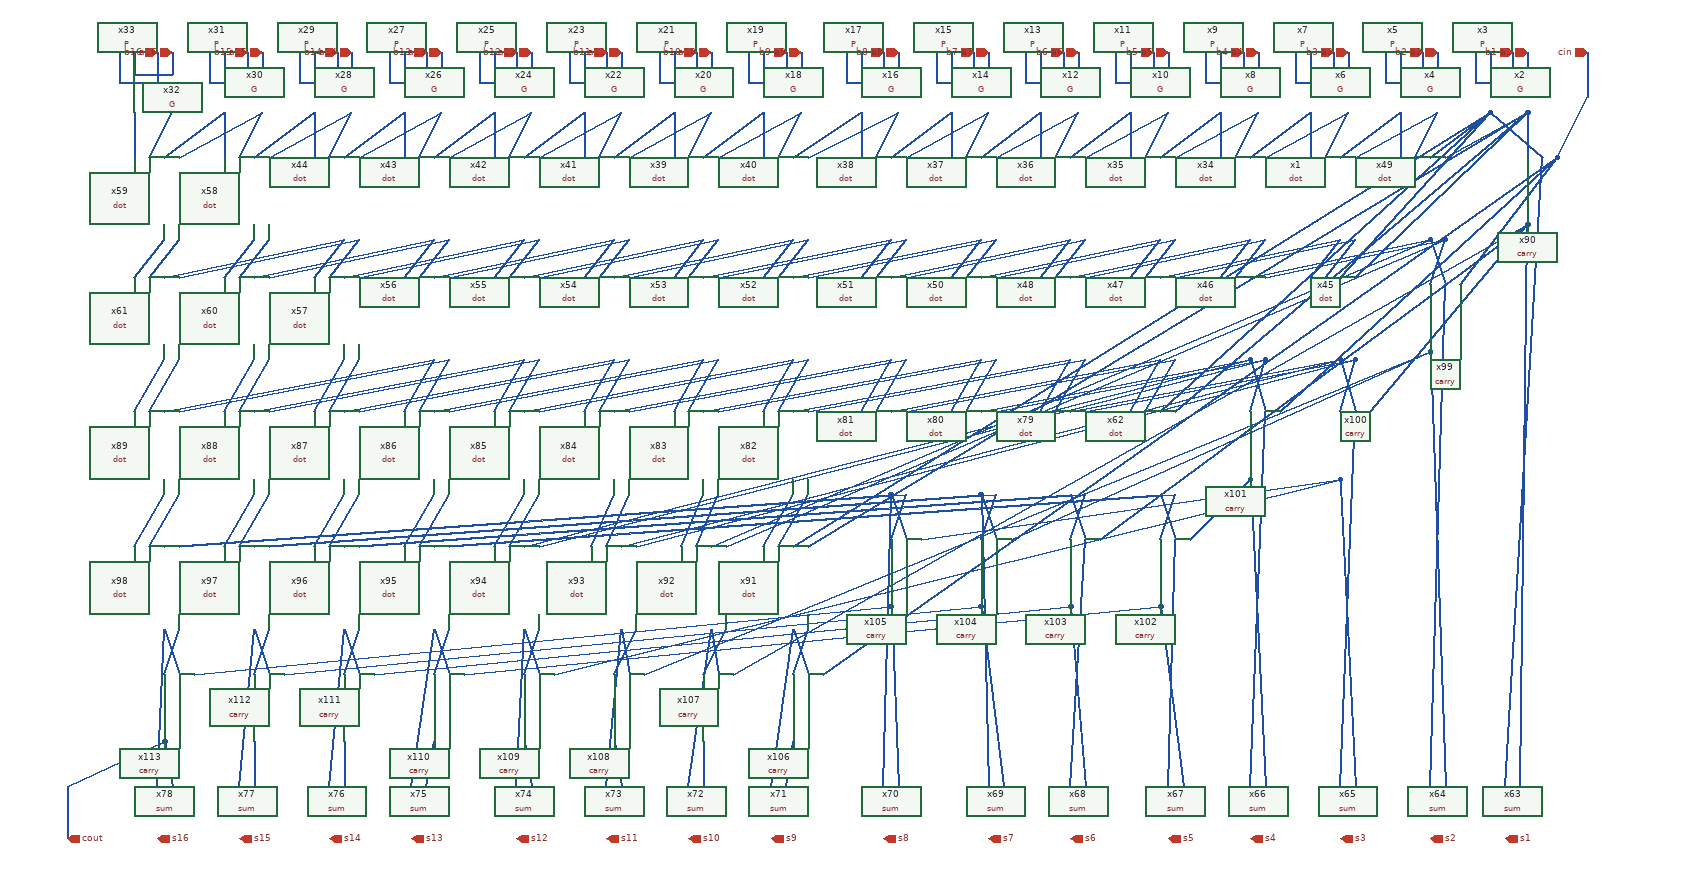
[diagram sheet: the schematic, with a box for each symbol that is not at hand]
v {xschem version=3.4.6 file_version=1.2}
G {}
K {}
V {}
S {}
E {}
N 1020 -110 1020 -50 {lab=cin}
N 940 -110 940 -80 {lab=a1}
N 890 -80 940 -80 {lab=a1}
N 890 -110 890 -80 {lab=a1}
N 920 -110 920 -70 {lab=b1}
N 870 -70 920 -70 {lab=b1}
N 870 -110 870 -70 {lab=b1}
N 820 -110 820 -80 {lab=a2}
N 770 -80 820 -80 {lab=a2}
N 770 -110 770 -80 {lab=a2}
N 800 -110 800 -70 {lab=b2}
N 750 -70 800 -70 {lab=b2}
N 750 -110 750 -70 {lab=b2}
N 700 -110 700 -80 {lab=a3}
N 650 -80 700 -80 {lab=a3}
N 650 -110 650 -80 {lab=a3}
N 680 -110 680 -70 {lab=b3}
N 630 -70 680 -70 {lab=b3}
N 630 -110 630 -70 {lab=b3}
N 580 -110 580 -80 {lab=a4}
N 530 -80 580 -80 {lab=a4}
N 530 -110 530 -80 {lab=a4}
N 560 -110 560 -70 {lab=b4}
N 510 -70 560 -70 {lab=b4}
N 510 -110 510 -70 {lab=b4}
N 460 -110 460 -80 {lab=a5}
N 410 -80 460 -80 {lab=a5}
N 410 -110 410 -80 {lab=a5}
N 440 -110 440 -70 {lab=b5}
N 390 -70 440 -70 {lab=b5}
N 390 -110 390 -70 {lab=b5}
N 340 -110 340 -80 {lab=a6}
N 290 -80 340 -80 {lab=a6}
N 290 -110 290 -80 {lab=a6}
N 320 -110 320 -70 {lab=b6}
N 270 -70 320 -70 {lab=b6}
N 270 -110 270 -70 {lab=b6}
N 220 -110 220 -80 {lab=a7}
N 170 -80 220 -80 {lab=a7}
N 170 -110 170 -80 {lab=a7}
N 200 -110 200 -70 {lab=b7}
N 150 -70 200 -70 {lab=b7}
N 150 -110 150 -70 {lab=b7}
N 100 -110 100 -80 {lab=a8}
N 50 -80 100 -80 {lab=a8}
N 50 -110 50 -80 {lab=a8}
N 80 -110 80 -70 {lab=b8}
N 30 -70 80 -70 {lab=b8}
N 30 -110 30 -70 {lab=b8}
N -30 -110 -30 -80 {lab=a9}
N -80 -80 -30 -80 {lab=a9}
N -80 -110 -80 -80 {lab=a9}
N -50 -110 -50 -70 {lab=b9}
N -100 -70 -50 -70 {lab=b9}
N -100 -110 -100 -70 {lab=b9}
N -150 -110 -150 -80 {lab=a10}
N -200 -80 -150 -80 {lab=a10}
N -200 -110 -200 -80 {lab=a10}
N -170 -110 -170 -70 {lab=b10}
N -220 -70 -170 -70 {lab=b10}
N -220 -110 -220 -70 {lab=b10}
N -270 -110 -270 -80 {lab=a11}
N -320 -80 -270 -80 {lab=a11}
N -320 -110 -320 -80 {lab=a11}
N -290 -110 -290 -70 {lab=b11}
N -340 -70 -290 -70 {lab=b11}
N -340 -110 -340 -70 {lab=b11}
N -390 -110 -390 -80 {lab=a12}
N -440 -80 -390 -80 {lab=a12}
N -440 -110 -440 -80 {lab=a12}
N -410 -110 -410 -70 {lab=b12}
N -460 -70 -410 -70 {lab=b12}
N -460 -110 -460 -70 {lab=b12}
N -510 -110 -510 -80 {lab=a13}
N -560 -80 -510 -80 {lab=a13}
N -560 -110 -560 -80 {lab=a13}
N -530 -110 -530 -70 {lab=b13}
N -580 -70 -530 -70 {lab=b13}
N -580 -110 -580 -70 {lab=b13}
N -630 -110 -630 -80 {lab=a14}
N -680 -80 -630 -80 {lab=a14}
N -680 -110 -680 -80 {lab=a14}
N -650 -110 -650 -70 {lab=b14}
N -700 -70 -650 -70 {lab=b14}
N -700 -110 -700 -70 {lab=b14}
N -750 -110 -750 -80 {lab=a15}
N -800 -80 -750 -80 {lab=a15}
N -800 -110 -800 -80 {lab=a15}
N -770 -110 -770 -70 {lab=b15}
N -820 -70 -770 -70 {lab=b15}
N -820 -110 -820 -70 {lab=b15}
N -870 -110 -870 -80 {lab=a16}
N -920 -80 -870 -80 {lab=a16}
N -920 -110 -920 -80 {lab=a16}
N -890 -110 -890 -70 {lab=b16}
N -940 -70 -890 -70 {lab=b16}
N -940 -110 -940 -70 {lab=b16}
N -1010 870 -1010 940 {lab=cout}
N 770 -30 770 30 {lab=#net1}
N 790 30 820 -30 {lab=#net2}
N 810 30 890 -30 {lab=#net3}
N 830 30 940 -30 {lab=#net4}
N 650 -30 650 30 {lab=#net5}
N 670 30 700 -30 {lab=#net6}
N 690 30 770 -30 {lab=#net1}
N 710 30 820 -30 {lab=#net2}
N 530 -30 530 30 {lab=#net7}
N 550 30 580 -30 {lab=#net8}
N 570 30 650 -30 {lab=#net5}
N 590 30 700 -30 {lab=#net6}
N 410 -30 410 30 {lab=#net9}
N 430 30 460 -30 {lab=#net10}
N 450 30 530 -30 {lab=#net7}
N 470 30 580 -30 {lab=#net8}
N 290 -30 290 30 {lab=#net11}
N 310 30 340 -30 {lab=#net12}
N 330 30 410 -30 {lab=#net9}
N 350 30 460 -30 {lab=#net10}
N 170 -30 170 30 {lab=#net13}
N 190 30 220 -30 {lab=#net14}
N 210 30 290 -30 {lab=#net11}
N 230 30 340 -30 {lab=#net12}
N 50 -30 50 30 {lab=#net15}
N 70 30 100 -30 {lab=#net16}
N 90 30 170 -30 {lab=#net13}
N 110 30 220 -30 {lab=#net14}
N -200 -30 -200 30 {lab=#net17}
N -180 30 -150 -30 {lab=#net18}
N -160 30 -80 -30 {lab=#net19}
N -140 30 -30 -30 {lab=#net20}
N -80 -30 -80 30 {lab=#net19}
N -60 30 -30 -30 {lab=#net20}
N -40 30 50 -30 {lab=#net15}
N -20 30 100 -30 {lab=#net16}
N -320 -30 -320 30 {lab=#net21}
N -300 30 -270 -30 {lab=#net22}
N -280 30 -200 -30 {lab=#net17}
N -260 30 -150 -30 {lab=#net18}
N -440 -30 -440 30 {lab=#net23}
N -420 30 -390 -30 {lab=#net24}
N -400 30 -320 -30 {lab=#net21}
N -380 30 -270 -30 {lab=#net22}
N -560 -30 -560 30 {lab=#net25}
N -540 30 -510 -30 {lab=#net26}
N -520 30 -440 -30 {lab=#net23}
N -500 30 -390 -30 {lab=#net24}
N -680 -30 -680 30 {lab=#net27}
N -660 30 -630 -30 {lab=#net28}
N -640 30 -560 -30 {lab=#net25}
N -620 30 -510 -30 {lab=#net26}
N 710 190 940 -30 {lab=#net4}
N 690 190 890 -30 {lab=#net3}
N 670 190 710 140 {lab=#net29}
N 650 190 690 140 {lab=#net30}
N 530 190 570 140 {lab=#net31}
N 550 190 590 140 {lab=#net32}
N 570 190 810 140 {lab=#net33}
N 590 190 830 140 {lab=#net34}
N 410 190 450 140 {lab=#net35}
N 430 190 470 140 {lab=#net36}
N 450 190 690 140 {lab=#net30}
N 470 190 710 140 {lab=#net29}
N 290 190 330 140 {lab=#net37}
N 310 190 350 140 {lab=#net38}
N 330 190 570 140 {lab=#net31}
N 350 190 590 140 {lab=#net32}
N 170 190 210 140 {lab=#net39}
N 190 190 230 140 {lab=#net40}
N 210 190 450 140 {lab=#net35}
N 230 190 470 140 {lab=#net36}
N 50 190 90 140 {lab=#net41}
N 70 190 110 140 {lab=#net42}
N 90 190 330 140 {lab=#net37}
N 110 190 350 140 {lab=#net38}
N -80 190 -40 140 {lab=#net43}
N -60 190 -20 140 {lab=#net44}
N -40 190 210 140 {lab=#net39}
N -20 190 230 140 {lab=#net40}
N -200 190 -160 140 {lab=#net45}
N -180 190 -140 140 {lab=#net46}
N -160 190 90 140 {lab=#net41}
N -140 190 110 140 {lab=#net42}
N -320 190 -280 140 {lab=#net47}
N -300 190 -260 140 {lab=#net48}
N -280 190 -40 140 {lab=#net43}
N -260 190 -20 140 {lab=#net44}
N -440 190 -400 140 {lab=#net49}
N -420 190 -380 140 {lab=#net50}
N -400 190 -160 140 {lab=#net45}
N -380 190 -140 140 {lab=#net46}
N -560 190 -520 140 {lab=#net51}
N -540 190 -500 140 {lab=#net52}
N -520 190 -280 140 {lab=#net47}
N -500 190 -260 140 {lab=#net48}
N -680 190 -640 140 {lab=#net53}
N -660 190 -620 140 {lab=#net54}
N -640 190 -400 140 {lab=#net49}
N -620 190 -380 140 {lab=#net50}
N -800 -30 -800 30 {lab=#net55}
N -780 30 -750 -30 {lab=#net56}
N -760 30 -680 -30 {lab=#net27}
N -740 30 -630 -30 {lab=#net28}
N -920 -30 -920 30 {lab=#net57}
N -900 30 -870 -30 {lab=#net58}
N -880 30 -800 -30 {lab=#net55}
N -860 30 -750 -30 {lab=#net56}
N -800 190 -760 140 {lab=#net59}
N -780 190 -740 140 {lab=#net60}
N -760 190 -520 140 {lab=#net51}
N -740 190 -500 140 {lab=#net52}
N -920 190 -880 140 {lab=#net61}
N -900 190 -860 140 {lab=#net62}
N -880 190 -640 140 {lab=#net53}
N -860 190 -620 140 {lab=#net54}
N 470 370 940 -30 {lab=#net4}
N 450 370 890 -30 {lab=#net3}
N 430 370 470 300 {lab=#net63}
N 410 370 450 300 {lab=#net64}
N 290 370 330 300 {lab=#net65}
N 310 370 350 300 {lab=#net66}
N 330 370 690 300 {lab=#net67}
N 350 370 710 300 {lab=#net68}
N 170 370 210 300 {lab=#net69}
N 190 370 230 300 {lab=#net70}
N 210 370 570 300 {lab=#net71}
N 230 370 590 300 {lab=#net72}
N 50 370 90 300 {lab=#net73}
N 70 370 110 300 {lab=#net74}
N 90 370 450 300 {lab=#net64}
N 110 370 470 300 {lab=#net63}
N -80 370 -40 300 {lab=#net75}
N -60 370 -20 300 {lab=#net76}
N -200 370 -160 300 {lab=#net77}
N -180 370 -140 300 {lab=#net78}
N -40 370 330 300 {lab=#net65}
N -20 370 350 300 {lab=#net66}
N -160 370 210 300 {lab=#net69}
N -140 370 230 300 {lab=#net70}
N -320 370 -280 300 {lab=#net79}
N -300 370 -260 300 {lab=#net80}
N -280 370 90 300 {lab=#net73}
N -260 370 110 300 {lab=#net74}
N -440 370 -400 300 {lab=#net81}
N -420 370 -380 300 {lab=#net82}
N -400 370 -40 300 {lab=#net75}
N -380 370 -20 300 {lab=#net76}
N -560 370 -520 300 {lab=#net83}
N -540 370 -500 300 {lab=#net84}
N -520 370 -160 300 {lab=#net77}
N -500 370 -140 300 {lab=#net78}
N -680 370 -640 300 {lab=#net85}
N -660 370 -620 300 {lab=#net86}
N -640 370 -280 300 {lab=#net79}
N -620 370 -260 300 {lab=#net80}
N -800 370 -760 300 {lab=#net87}
N -780 370 -740 300 {lab=#net88}
N -760 370 -400 300 {lab=#net81}
N -740 370 -380 300 {lab=#net82}
N -920 370 -880 300 {lab=#net89}
N -900 370 -860 300 {lab=#net90}
N -880 370 -520 300 {lab=#net83}
N -860 370 -500 300 {lab=#net84}
N 940 -30 940 30 {lab=#net4}
N 890 -30 960 30 {lab=#net3}
N 980 30 1020 -50 {lab=cin}
N -20 550 940 -30 {lab=#net4}
N -40 550 890 -30 {lab=#net3}
N -80 550 -40 480 {lab=#net91}
N -60 550 -20 480 {lab=#net92}
N -190 550 -160 480 {lab=#net93}
N -170 550 -140 480 {lab=#net94}
N -150 550 810 140 {lab=#net33}
N -130 550 830 140 {lab=#net34}
N -310 550 -280 480 {lab=#net95}
N -290 550 -260 480 {lab=#net96}
N -270 550 690 300 {lab=#net67}
N -250 550 710 300 {lab=#net68}
N -440 550 -400 480 {lab=#net97}
N -420 550 -380 480 {lab=#net98}
N -400 550 570 300 {lab=#net71}
N -380 550 590 300 {lab=#net72}
N -560 550 -520 480 {lab=#net99}
N -540 550 -500 480 {lab=#net100}
N -520 550 450 480 {lab=#net101}
N -500 550 470 480 {lab=#net102}
N -680 550 -640 480 {lab=#net103}
N -660 550 -620 480 {lab=#net104}
N -640 550 330 480 {lab=#net105}
N -620 550 350 480 {lab=#net106}
N -800 550 -760 480 {lab=#net107}
N -780 550 -740 480 {lab=#net108}
N -760 550 210 480 {lab=#net109}
N -740 550 230 480 {lab=#net110}
N -920 550 -880 480 {lab=#net111}
N -900 550 -860 480 {lab=#net112}
N -880 550 90 480 {lab=#net113}
N -860 550 110 480 {lab=#net114}
N 810 200 830 140 {lab=#net34}
N 810 140 830 200 {lab=#net33}
N 570 370 590 300 {lab=#net72}
N 570 300 590 370 {lab=#net71}
N 690 370 710 300 {lab=#net68}
N 690 300 710 370 {lab=#net67}
N 610 370 980 30 {lab=cin}
N 450 540 470 480 {lab=#net102}
N 450 480 470 540 {lab=#net101}
N 490 540 570 460 {lab=#net115}
N 330 540 350 480 {lab=#net106}
N 330 480 350 540 {lab=#net105}
N 850 200 980 30 {lab=cin}
N 730 370 940 120 {lab=#net116}
N 370 540 940 120 {lab=#net116}
N 250 540 810 290 {lab=#net117}
N 130 540 690 460 {lab=#net118}
N 210 480 230 540 {lab=#net109}
N 210 540 230 480 {lab=#net110}
N 90 480 110 540 {lab=#net113}
N 90 540 110 480 {lab=#net114}
N 0 720 980 30 {lab=cin}
N -120 720 940 120 {lab=#net116}
N -240 720 810 290 {lab=#net117}
N -360 720 690 460 {lab=#net118}
N -480 720 450 630 {lab=#net119}
N -600 720 330 630 {lab=#net120}
N -720 720 210 630 {lab=#net121}
N -840 720 90 630 {lab=#net122}
N -880 660 -860 720 {lab=#net123}
N -880 720 -860 660 {lab=#net124}
N -760 660 -740 720 {lab=#net125}
N -760 720 -740 660 {lab=#net126}
N -640 660 -620 720 {lab=#net127}
N -640 720 -620 660 {lab=#net128}
N -520 660 -500 720 {lab=#net129}
N -520 720 -500 660 {lab=#net130}
N -400 660 -380 720 {lab=#net131}
N -400 720 -380 660 {lab=#net132}
N -270 660 -260 720 {lab=#net133}
N -280 720 -250 660 {lab=#net134}
N -160 720 -130 660 {lab=#net135}
N -150 660 -140 720 {lab=#net136}
N -40 720 -20 660 {lab=#net137}
N -40 660 -20 720 {lab=#net138}
N -880 810 -870 870 {lab=cout}
N -890 870 -880 660 {lab=#net123}
N -780 870 -760 660 {lab=#net125}
N -760 810 -760 870 {lab=#net139}
N -660 870 -640 660 {lab=#net127}
N -640 810 -640 870 {lab=#net140}
N -550 870 -520 660 {lab=#net129}
N -530 870 -520 810 {lab=#net141}
N -400 810 -390 870 {lab=#net142}
N -410 870 -400 660 {lab=#net131}
N -280 810 -270 870 {lab=#net143}
N -290 870 -270 660 {lab=#net133}
N -160 810 -160 870 {lab=#net144}
N -180 870 -150 660 {lab=#net136}
N -50 870 -40 810 {lab=#net145}
N -70 870 -40 660 {lab=#net138}
N 90 630 100 870 {lab=#net122}
N 80 870 90 480 {lab=#net113}
N 210 480 220 870 {lab=#net109}
N 210 630 240 870 {lab=#net121}
N 330 630 350 870 {lab=#net120}
N 330 870 350 540 {lab=#net105}
N 450 630 480 870 {lab=#net119}
N 460 870 470 540 {lab=#net101}
N 570 460 590 870 {lab=#net115}
N 570 870 590 370 {lab=#net71}
N 690 470 710 870 {lab=#net118}
N 690 870 710 370 {lab=#net67}
N 810 290 830 870 {lab=#net117}
N 810 870 830 200 {lab=#net33}
N 930 870 940 120 {lab=#net116}
N 910 870 960 30 {lab=#net3}
N -1010 870 -880 810 {lab=cout}
N 940 120 940 130 {lab=#net116}
N 810 290 810 300 {lab=#net117}
N 90 630 90 640 {lab=#net122}
N 450 630 450 640 {lab=#net119}
N 330 630 330 640 {lab=#net120}
N 570 460 570 470 {lab=#net115}
N 690 460 690 470 {lab=#net118}
N 210 630 210 640 {lab=#net121}
N -520 810 -520 820 {lab=#net141}
N -400 810 -400 820 {lab=#net142}
N -280 810 -280 820 {lab=#net143}
N -880 810 -880 820 {lab=cout}
N -40 810 -40 820 {lab=#net145}
C {G.sym} 930 -70 1 0 {name=x2}
C {P.sym} 880 -70 1 0 {name=x3}
C {G.sym} 810 -70 1 0 {name=x4}
C {P.sym} 760 -70 1 0 {name=x5}
C {G.sym} 690 -70 1 0 {name=x6}
C {P.sym} 640 -70 1 0 {name=x7}
C {G.sym} 570 -70 1 0 {name=x8}
C {P.sym} 520 -70 1 0 {name=x9}
C {G.sym} 450 -70 1 0 {name=x10}
C {P.sym} 400 -70 1 0 {name=x11}
C {G.sym} 330 -70 1 0 {name=x12}
C {P.sym} 280 -70 1 0 {name=x13}
C {G.sym} 210 -70 1 0 {name=x14}
C {P.sym} 160 -70 1 0 {name=x15}
C {G.sym} 90 -70 1 0 {name=x16}
C {P.sym} 40 -70 1 0 {name=x17}
C {G.sym} -40 -70 1 0 {name=x18}
C {P.sym} -90 -70 1 0 {name=x19}
C {G.sym} -160 -70 1 0 {name=x20}
C {P.sym} -210 -70 1 0 {name=x21}
C {G.sym} -280 -70 1 0 {name=x22}
C {P.sym} -330 -70 1 0 {name=x23}
C {G.sym} -400 -70 1 0 {name=x24}
C {P.sym} -450 -70 1 0 {name=x25}
C {G.sym} -520 -70 1 0 {name=x26}
C {P.sym} -570 -70 1 0 {name=x27}
C {G.sym} -640 -70 1 0 {name=x28}
C {P.sym} -690 -70 1 0 {name=x29}
C {G.sym} -760 -70 1 0 {name=x30}
C {P.sym} -810 -70 1 0 {name=x31}
C {G.sym} -880 -70 1 0 {name=x32}
C {P.sym} -930 -70 1 0 {name=x33}
C {sum.sym} 920 900 3 1 {name=x63}
C {sum.sym} 820 900 3 1 {name=x64}
C {sum.sym} 700 900 3 1 {name=x65}
C {sum.sym} 580 900 3 1 {name=x66}
C {sum.sym} 470 900 3 1 {name=x67}
C {sum.sym} 340 900 3 1 {name=x68}
C {sum.sym} 230 900 3 1 {name=x69}
C {sum.sym} 90 900 3 1 {name=x70}
C {sum.sym} -60 900 3 1 {name=x71}
C {sum.sym} -170 900 3 1 {name=x72}
C {sum.sym} -280 900 3 1 {name=x73}
C {sum.sym} -400 900 3 1 {name=x74}
C {sum.sym} -540 900 3 1 {name=x75}
C {sum.sym} -650 900 3 1 {name=x76}
C {sum.sym} -770 900 3 1 {name=x77}
C {sum.sym} -880 900 3 1 {name=x78}
C {ipin.sym} -890 -110 1 0 {name=p3 lab=b16}
C {ipin.sym} -870 -110 1 0 {name=p4 lab=a16}
C {ipin.sym} -770 -110 1 0 {name=p7 lab=b15}
C {ipin.sym} -750 -110 1 0 {name=p8 lab=a15}
C {ipin.sym} -650 -110 1 0 {name=p11 lab=b14}
C {ipin.sym} -630 -110 1 0 {name=p12 lab=a14}
C {ipin.sym} -530 -110 1 0 {name=p15 lab=b13}
C {ipin.sym} -510 -110 1 0 {name=p16 lab=a13}
C {ipin.sym} -410 -110 1 0 {name=p19 lab=b12}
C {ipin.sym} -390 -110 1 0 {name=p20 lab=a12}
C {ipin.sym} -290 -110 1 0 {name=p23 lab=b11}
C {ipin.sym} -270 -110 1 0 {name=p24 lab=a11}
C {ipin.sym} -170 -110 1 0 {name=p27 lab=b10}
C {ipin.sym} -150 -110 1 0 {name=p28 lab=a10}
C {ipin.sym} -50 -110 1 0 {name=p31 lab=b9}
C {ipin.sym} -30 -110 1 0 {name=p32 lab=a9}
C {ipin.sym} 80 -110 1 0 {name=p35 lab=b8}
C {ipin.sym} 100 -110 1 0 {name=p36 lab=a8}
C {ipin.sym} 200 -110 1 0 {name=p39 lab=b7}
C {ipin.sym} 220 -110 1 0 {name=p40 lab=a7}
C {ipin.sym} 320 -110 1 0 {name=p43 lab=b6}
C {ipin.sym} 340 -110 1 0 {name=p44 lab=a6}
C {ipin.sym} 440 -110 1 0 {name=p47 lab=b5}
C {ipin.sym} 460 -110 1 0 {name=p48 lab=a5}
C {ipin.sym} 560 -110 1 0 {name=p51 lab=b4}
C {ipin.sym} 580 -110 1 0 {name=p52 lab=a4}
C {ipin.sym} 680 -110 1 0 {name=p55 lab=b3}
C {ipin.sym} 700 -110 1 0 {name=p56 lab=a3}
C {ipin.sym} 800 -110 1 0 {name=p59 lab=b2}
C {ipin.sym} 820 -110 1 0 {name=p60 lab=a2}
C {ipin.sym} 920 -110 1 0 {name=p63 lab=b1}
C {ipin.sym} 940 -110 1 0 {name=p64 lab=a1}
C {ipin.sym} 1020 -110 1 0 {name=p65 lab=cin}
C {opin.sym} 910 940 1 0 {name=p1 lab=s1}
C {opin.sym} 810 940 1 0 {name=p2 lab=s2}
C {opin.sym} 690 940 1 0 {name=p5 lab=s3}
C {opin.sym} 570 940 1 0 {name=p6 lab=s4}
C {opin.sym} 460 940 1 0 {name=p9 lab=s5}
C {opin.sym} 330 940 1 0 {name=p10 lab=s6}
C {opin.sym} 220 940 1 0 {name=p13 lab=s7}
C {opin.sym} 80 940 1 0 {name=p14 lab=s8}
C {opin.sym} -70 940 1 0 {name=p17 lab=s9}
C {opin.sym} -180 940 1 0 {name=p18 lab=s10}
C {opin.sym} -290 940 1 0 {name=p21 lab=s11}
C {opin.sym} -410 940 1 0 {name=p22 lab=s12}
C {opin.sym} -550 940 1 0 {name=p25 lab=s13}
C {opin.sym} -660 940 1 0 {name=p26 lab=s14}
C {opin.sym} -780 940 1 0 {name=p29 lab=s15}
C {opin.sym} -890 940 1 0 {name=p30 lab=s16}
C {opin.sym} -1010 940 1 0 {name=p33 lab=cout}
C {dot.sym} 800 90 1 0 {name=x49}
C {dot.sym} 680 90 1 0 {name=x1}
C {dot.sym} 560 90 1 0 {name=x34}
C {dot.sym} 440 90 1 0 {name=x35}
C {dot.sym} 320 90 1 0 {name=x36}
C {dot.sym} 200 90 1 0 {name=x37}
C {dot.sym} 80 90 1 0 {name=x38}
C {dot.sym} -170 90 1 0 {name=x39}
C {dot.sym} -50 90 1 0 {name=x40}
C {dot.sym} -290 90 1 0 {name=x41}
C {dot.sym} -410 90 1 0 {name=x42}
C {dot.sym} -530 90 1 0 {name=x43}
C {dot.sym} -650 90 1 0 {name=x44}
C {dot.sym} 680 250 1 0 {name=x45}
C {dot.sym} 560 250 1 0 {name=x46}
C {dot.sym} 440 250 1 0 {name=x47}
C {dot.sym} 320 250 1 0 {name=x48}
C {dot.sym} 200 250 1 0 {name=x50}
C {dot.sym} 80 250 1 0 {name=x51}
C {dot.sym} -50 250 1 0 {name=x52}
C {dot.sym} -170 250 1 0 {name=x53}
C {dot.sym} -290 250 1 0 {name=x54}
C {dot.sym} -410 250 1 0 {name=x55}
C {dot.sym} -530 250 1 0 {name=x56}
C {dot.sym} -650 250 1 0 {name=x57}
C {dot.sym} -770 90 1 0 {name=x58}
C {dot.sym} -890 90 1 0 {name=x59}
C {dot.sym} -770 250 1 0 {name=x60}
C {dot.sym} -890 250 1 0 {name=x61}
C {dot.sym} 440 430 1 0 {name=x62}
C {dot.sym} 320 430 1 0 {name=x79}
C {dot.sym} 200 430 1 0 {name=x80}
C {dot.sym} 80 430 1 0 {name=x81}
C {dot.sym} -50 430 1 0 {name=x82}
C {dot.sym} -170 430 1 0 {name=x83}
C {dot.sym} -290 430 1 0 {name=x84}
C {dot.sym} -410 430 1 0 {name=x85}
C {dot.sym} -530 430 1 0 {name=x86}
C {dot.sym} -650 430 1 0 {name=x87}
C {dot.sym} -770 430 1 0 {name=x88}
C {dot.sym} -890 430 1 0 {name=x89}
C {carry.sym} 960 80 3 1 {name=x90}
C {dot.sym} -50 610 1 0 {name=x91}
C {dot.sym} -160 610 1 0 {name=x92}
C {dot.sym} -280 610 1 0 {name=x93}
C {dot.sym} -410 610 1 0 {name=x94}
C {dot.sym} -530 610 1 0 {name=x95}
C {dot.sym} -650 610 1 0 {name=x96}
C {dot.sym} -770 610 1 0 {name=x97}
C {dot.sym} -890 610 1 0 {name=x98}
C {carry.sym} 830 250 3 1 {name=x99}
C {carry.sym} 710 420 3 1 {name=x100}
C {carry.sym} 590 420 3 1 {name=x101}
C {carry.sym} 470 590 3 1 {name=x102}
C {carry.sym} 350 590 3 1 {name=x103}
C {carry.sym} 230 590 3 1 {name=x104}
C {carry.sym} 110 590 3 1 {name=x105}
C {carry.sym} -20 770 3 1 {name=x106}
C {carry.sym} -140 770 3 1 {name=x107}
C {carry.sym} -260 770 3 1 {name=x108}
C {carry.sym} -380 770 3 1 {name=x109}
C {carry.sym} -500 770 3 1 {name=x110}
C {carry.sym} -620 770 3 1 {name=x111}
C {carry.sym} -740 770 3 1 {name=x112}
C {carry.sym} -860 770 3 1 {name=x113}
